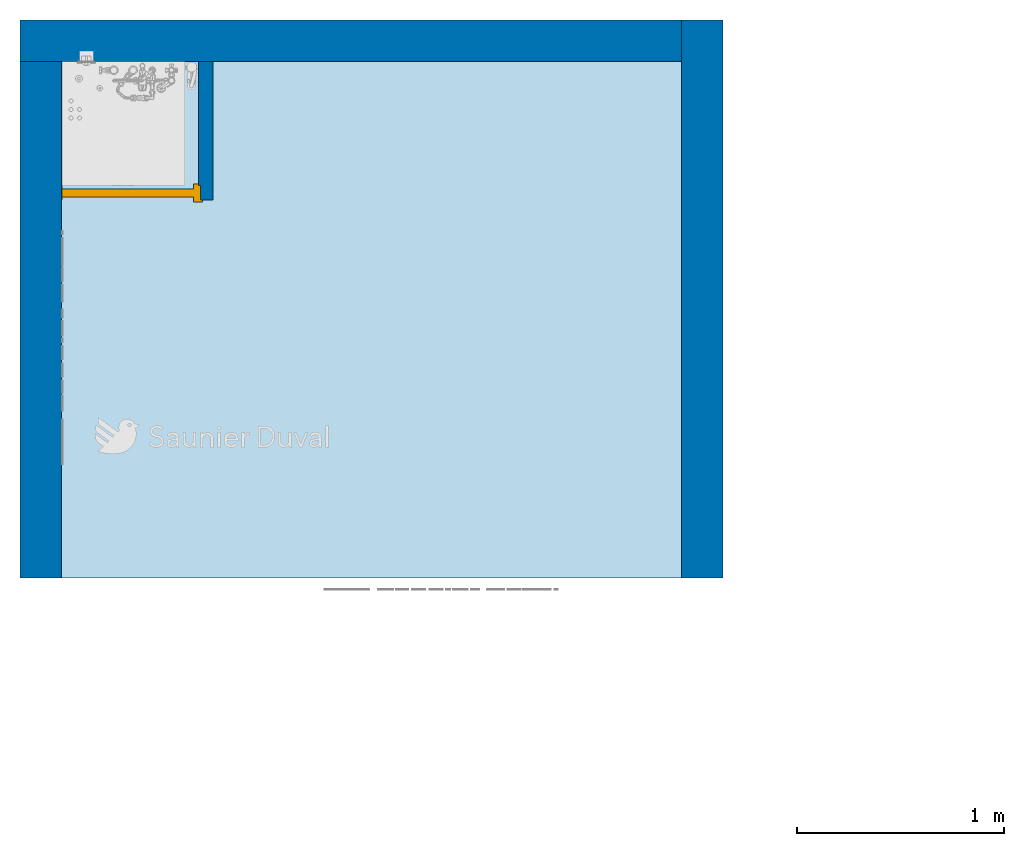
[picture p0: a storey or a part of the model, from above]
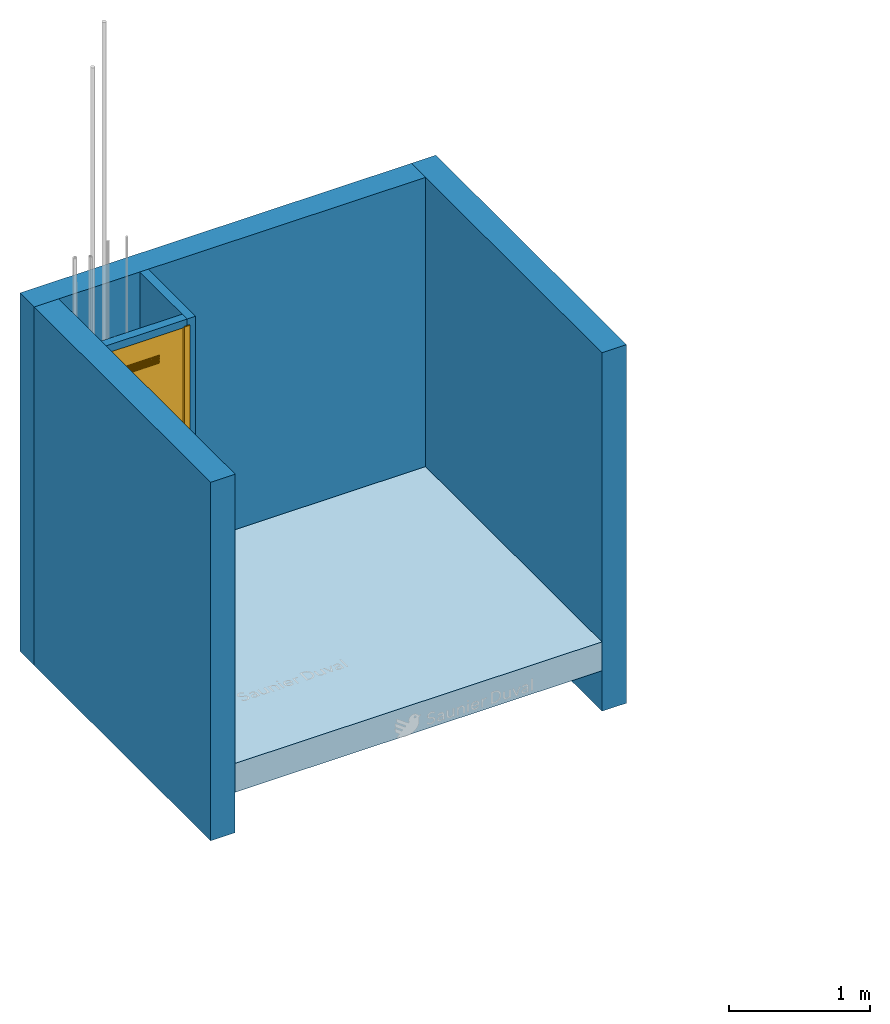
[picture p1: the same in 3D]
Properties of the parts of a building model (IFC2X3)

# File
Description: ViewDefinition [CoordinationView_V2.0], RevitIdentifiers [VersionGUID: 2ef846fa-e14e-409f-9a48-89c0e144c9c5, NumberOfSaves: 159], CoordinateReference [CoordinateBase: Coordonnées partagées]
File name: 0001
Time: 2024-07-12T12:26:03+01:00
Written by: ODA SDAI 24.6
Made in: Autodesk Revit 24.2.0.63 (FRA) - IFC 24.2.0.63

# IfcProject, 0001
LongName: Salle de formation PAC SD; Phase: Etat du projet

# IfcSite, Default
RefLatitude: 48, 52, 0, 117187; RefLongitude: 2, 19, 59, 880409; RefElevation: 0 m

# IfcBuilding
Pset_BuildingCommon - NumberOfStoreys: 1

# IfcBuildingStorey: Niveau:Ligne du Niveau (3)
Name | LongName | Elevation (m)
Niveau 0 | Niveau 0 | -1.94916e-14
Niveau 1 | Niveau 1 | 2.5
Niveau 2 | Niveau 2 | 6

# IfcBuildingElementProxy: Legrand Boite encastrement batibox 1 poste1:1 poste, Legrand Boite encastrement batibox 1 poste1:1 poste:1104890
In: Niveau 0
Type - Material: Plastique orange
Type - Pset_ManufacturerTypeInformation - Manufacturer: Legrand
Pset_BuildingElementProxyCommon - Reference: 1 poste; sets with these values: 2

# IfcBuildingElementProxy: Legrand Sorties de câbles:Prise courant, Legrand Sorties de câbles:Prise courant:1104889
In: Niveau 0
Type - Material: Plastique, blanc opaque, Plastique, noir opaque
Type - Pset_ManufacturerTypeInformation - Manufacturer: Legrand
Pset_BuildingElementProxyCommon - Reference: Prise courant; sets with these values: 2

# IfcBuildingElementProxy: Legrand plaque2:1 poste, Legrand plaque2:1 poste:1104891
In: Niveau 0
Type - Material: Plastique, blanc opaque
Type - Pset_ManufacturerTypeInformation - Manufacturer: Legrand
Pset_BuildingElementProxyCommon - Reference: 1 poste; sets with these values: 2

# IfcBuildingElementProxy: Legrand support universel-20181:1 poste, Legrand support universel-20181:1 poste:1104892
In: Niveau 0
Type - Material: Plastique, noir opaque
Type - Pset_ManufacturerTypeInformation - Manufacturer: Legrand
Pset_BuildingElementProxyCommon - Reference: 1 poste; sets with these values: 2

# IfcBuildingElementProxy: Logo_Geometry_SD_3Dx10-:Mur_horizontal (2)
In: Niveau 0
Type - Material: Color RGB 251-026-031, Color RGB 10-10-10
Pset_BuildingElementProxyCommon - Reference: Mur_horizontal; sets with these values: 2
Name (Logo_Geometry_SD_3Dx10-:Mur_horizontal:...)
1134503
1151157

# IfcBuildingElementProxy: Logo_Geometry_SD_3Dx10-:Mur_vertical, Logo_Geometry_SD_3Dx10-:Mur_vertical:1135930
In: Niveau 0
Type - Material: Color RGB 251-026-031, Color RGB 10-10-10
Pset_BuildingElementProxyCommon - Reference: Mur_vertical; sets with these values: 2

# IfcBuildingElementProxy: Logo_Geometry_SD_3Dx10-:Sol, Logo_Geometry_SD_3Dx10-:Sol:1137777
In: Niveau 0
Type - Material: Color RGB 251-026-031, Color RGB 10-10-10
Pset_BuildingElementProxyCommon - Reference: Sol; sets with these values: 2

# IfcCovering: Isolation des canalisations:Par défaut (2)
In: Niveau 0
Type - PredefinedType: INSULATION
Material: Matériau du rendu 255-255-255
Pset_CoveringCommon - Reference: Par défaut; sets with these values: 2
Name (Isolation des canalisations:Par défaut:...)
1088362
1088377

# IfcDistributionPort (33)
Description: Flow
Name | FlowDirection | Group
Port_530808_1 | SOURCEANDSINK | Alimentation hydraulique 3
Port_530808_2 | SOURCEANDSINK | Alimentation hydraulique 3
OutPort_1087751_3 | SOURCE | Sanitaire 12
Port_1087751_4 | SOURCEANDSINK | Sanitaire 12
Port_1087754_0 | SOURCEANDSINK | Sanitaire 18
Port_1087754_1 | SOURCEANDSINK | Sanitaire 18
InPort_1087760_0 | SINK | Retour hydraulique 12
OutPort_1120095_17 | SOURCE | Retour hydraulique 12
OutPort_1087760_1 | SOURCE | Retour hydraulique 12
Port_1087775_0 | SOURCEANDSINK | Eau Chaude Sanitaire 5
Port_1087775_1 | SOURCEANDSINK | Eau Chaude Sanitaire 5
Port_1087777_0 | SOURCEANDSINK | Eau Froide Sanitaire 18
Port_1087777_1 | SOURCEANDSINK | Eau Froide Sanitaire 18
InPort_1087789_0 | SINK | Alimentation hydraulique 18
OutPort_1120095_21 | SOURCE | Alimentation hydraulique 18
OutPort_1087789_1 | SOURCE | Alimentation hydraulique 18
InPort_1120095_22 | SINK | Sanitaire 14
OutPort_1087816_0 | SOURCE | Sanitaire 14
InPort_1087816_1 | SINK | Sanitaire 14
Port_1087818_0 | SOURCEANDSINK | Sanitaire 16
Port_1087818_1 | SOURCEANDSINK | Sanitaire 16
Port_1087820_0 | SOURCEANDSINK | Alimentation hydraulique 17
Port_1087820_1 | SOURCEANDSINK | Alimentation hydraulique 17
InPort_1120095_10 | SINK
OutPort_1120095_11 | SOURCE
OutPort_1120095_16 | SOURCE
InPort_1120095_18 | SINK
OutPort_1120095_19 | SOURCE
InPort_1120095_20 | SINK
InPort_1120095_23 | SINK
OutPort_1120095_24 | SOURCE
OutPort_1120095_25 | SOURCE
Port_1120095_26 | SOURCEANDSINK

# IfcDoor: Va et vient simple - Panneau plein_GM:0.55m x 2.40m, Va et vient simple - Panneau plein_GM:0.55m x 2.40m:1142449
In: Niveau 0
Type - OperationType: DOUBLE_SWING_RIGHT; ParameterTakesPrecedence: no; Sizeable: no; Material: Plastique, blanc opaque, Verre
Type - Va et vient simple - Panneau plein_GM:0.55m x 2.40m:1142449:1 - PanelOperation: DOUBLE_ACTING
Type - Pset_DoorCommon - IsExternal: no; ThermalTransmittance: 3.7021 kg/K/s3
OverallHeight: 2.435 m; OverallWidth: 0.67 m
Pset_DoorCommon - Reference: 0.55m x 2.40m
Pset_QuantityTakeOff - Reference: 0.55m x 2.40m

# IfcFlowController: Siphon 32:Siphon 32, Siphon 32:Siphon 32:1087751
In: Niveau 0
Type - Material: <Unnamed>
Type - Pset_ManufacturerTypeInformation - Manufacturer: GIRPI
Pset_DistributionFlowElementCommon - Reference: Siphon 32; sets with these values: 2
Group: Sanitaire 12

# IfcFlowFitting: Coude - tube frigo:Standard, Coude - tube frigo:Standard:530808
In: Niveau 0
Type - Material: Cuivre
Pset_DistributionFlowElementCommon - Reference: Standard; sets with these values: 2
Group: Alimentation hydraulique 3

# IfcFlowMovingDevice: HC_Heat Pump_GM_Saunier Duval_GeniaSet TEK_IS_kit complet+2C:HA 10-7_2 STB, HC_Heat Pump_GM_Saunier Duval_GeniaSet TEK_IS_kit complet+2C:HA 10-7_2 STB:1120095
In: Niveau 0
Type - Material: Color RGB 121-121-121, Color RGB 244-244-244, Color RGB 116-051-029, Color RGB 040-040-040, Color RGB 251-026-031, Color RGB 191-153-066
Type - Pset_ManufacturerTypeInformation - Manufacturer: Saunier Duval
Material: Color RGB 191-153-066, Color RGB 040-040-040, Color RGB 000-000-255, Color RGB 116-051-029, <Unnamed>, Color RGB 120-120-120, Color RGB 251-026-031, Color RGB 121-121-121, Color RGB 244-244-244; Group: Retour hydraulique 12; Alimentation hydraulique 18; Sanitaire 14
Pset_DistributionFlowElementCommon - Reference: HA 10-7_2 STB; sets with these values: 2

# IfcFlowSegment: Canalisation souple arrondie:Souple - Circulaire, Canalisation souple arrondie:Souple - Circulaire:1087818
In: Niveau 0
Type - PredefinedType: FLEXIBLESEGMENT
Pset_DistributionFlowElementCommon - Reference: Souple - Circulaire; sets with these values: 2
Group: Sanitaire 16

# IfcFlowSegment: Canalisation:COMAP MULTISKIN - SKINPRESS Laiton (3)
In: Niveau 0
Type - Pset_ManufacturerTypeInformation - Manufacturer: COMAP
Pset_DistributionFlowElementCommon - Reference: COMAP MULTISKIN - SKINPRESS Laiton; sets with these values: 2
Pset_FlowSegmentDuctSegment - sets with these values: 2
Name (Canalisation:COMAP MULTISKIN - SKINPRESS Laiton:...) | Length (m) | Group
1087760 | 2.42322 | Retour hydraulique 12
1087777 | 0.862353 | Eau Froide Sanitaire 18
1087820 | 2.77697 | Alimentation hydraulique 17

# IfcFlowSegment: Canalisation:Cuivre Frigo (2)
In: Niveau 0
Pset_DistributionFlowElementCommon - Reference: Cuivre Frigo; sets with these values: 2
Pset_FlowSegmentDuctSegment - sets with these values: 2
Name (Canalisation:Cuivre Frigo:...) | Length (m) | Group
1087789 | 0.948862 | Alimentation hydraulique 18
1087816 | 0.933862 | Sanitaire 14

# IfcFlowSegment: Canalisation:Mutlicouche_GM, Canalisation:Mutlicouche_GM:1087775
In: Niveau 0
Type - Pset_ManufacturerTypeInformation - Manufacturer: Comap
Pset_DistributionFlowElementCommon - Reference: Mutlicouche_GM; sets with these values: 2
Pset_FlowSegmentDuctSegment - Length: 0.914998 m; sets with these values: 2
Group: Eau Chaude Sanitaire 5

# IfcFlowSegment: Canalisation:PVC - DWV, Canalisation:PVC - DWV:1087754
In: Niveau 0
Pset_DistributionFlowElementCommon - Reference: PVC - DWV; sets with these values: 2
Pset_FlowSegmentDuctSegment - Length: 0.35 m; sets with these values: 2
Group: Sanitaire 18

# IfcOpeningElement: Opening (3)
In: Niveau 0
Name | Reference | sets with these values
Mur de base:Générique - Ext. 200 mm:1087687 | 0.55m x 2.40m | 2
Mur de base:Générique - Int. 70 mm:1087773 | 0.55m x 2.40m | 2
Va et vient simple - Panneau plein_GM:0.55m x 2.40m:1142449:1

# IfcOpeningElement: Recess, Mur de base:Générique - Ext. 200 mm:1087686
In: Niveau 0
Pset_OpeningElementCommon - Reference: 1 poste; sets with these values: 2

# IfcSlab: Sol:Dalle en béton - 250 mm, Sol:Dalle en béton - 250 mm:1087690
In: Niveau 0
Type - PredefinedType: FLOOR; Material: Maçonnerie - Béton 0.25 m
Type - Pset_SlabCommon - IsExternal: no
Pset_QuantityTakeOff - Reference: Dalle en béton - 250 mm; sets with these values: 2
Pset_SlabCommon - LoadBearing: yes; Reference: Dalle en béton - 250 mm; PitchAngle: 0 deg

# IfcWallStandardCase: Mur de base:Générique - Ext. 200 mm (3)
In: Niveau 0
Type - PredefinedType: STANDARD; Material: Mur par défaut 0.2 m, Color RGB 255-255-255 0.001 m
Type - Pset_WallCommon - IsExternal: yes
Pset_QuantityTakeOff - Reference: Générique - Ext. 200 mm; sets with these values: 2
Pset_WallCommon - Reference: Générique - Ext. 200 mm; ExtendToStructure: no; LoadBearing: yes
Name (Mur de base:Générique - Ext. 200 mm:...)
1087685
1087686
1087687

# IfcWallStandardCase: Mur de base:Générique - Int. 70 mm (2)
In: Niveau 0
Type - PredefinedType: STANDARD; Material: Mur par défaut 0.07 m
Type - Pset_WallCommon - IsExternal: no
Pset_QuantityTakeOff - Reference: Générique - Int. 70 mm; sets with these values: 2
Pset_WallCommon - ExtendToStructure: no; Reference: Générique - Int. 70 mm
Name (Mur de base:Générique - Int. 70 mm:...) | LoadBearing
1087773 | no
1138425 | yes
